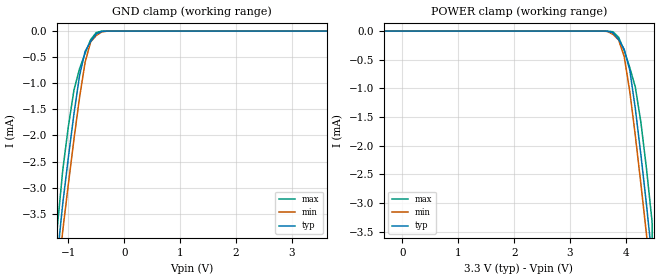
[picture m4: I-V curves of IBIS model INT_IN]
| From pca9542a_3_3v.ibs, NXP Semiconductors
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[Model]   INT_IN
Model_type Input
Vinh=2.1
Vinl=0.9
C_comp   1.73p   1.73p   1.73p
[Temperature Range] 27   85   -40
[Voltage Range]   3.3   2.97   3.63
[POWER Clamp Reference]3.3   2.97   3.63
[GND Clamp Reference]0   0   0
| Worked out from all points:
|   GND clamp passes 1 mA (typ) near -0.82 V on its own axis
[GND Clamp]
-2V       -10.28A    -9.162A    -11.7A
-1.2V     -4.351mA   -4.856mA   -3.782mA
-1.1V     -3.3mA     -3.822mA   -2.661mA
-1V       -2.42mA    -2.932mA   -1.826mA
-900mV    -1.587mA   -2.076mA   -1.131mA
-800mV    -856.5uA   -1.274mA   -722.8uA
-700mV    -388.8uA   -596.3uA   -423.6uA
-600mV    -199uA     -205.2uA   -162.8uA
-500mV    -55.95uA   -84.45uA   -27.01uA
-400mV    -5.314uA   -14.58uA   -847.7nA
-300mV    -147nA     -737.1nA   -8.808nA
3.63V     11.85pA    25pA       10.9pA
[POWER Clamp]
-330mV    11.85pA    25pA       10.9pA
3.57V     -44.33nA   -254nA     -2.09nA
3.77V     -31.95uA   -57.22uA   -11.54uA
3.87V     -148.2uA   -153.7uA   -107.4uA
3.97V     -316.4uA   -440.3uA   -335.2uA
4.07V     -678.5uA   -1.053mA   -636uA
4.17V     -1.353mA   -1.828mA   -977.2uA
4.27V     -2.164mA   -2.671mA   -1.596mA
4.37V     -3.032mA   -3.551mA   -2.402mA
4.47V     -3.974mA   -4.499mA   -3.329mA
4.57V     -7.118mA   -6.673mA   -11.82mA
5.27V     -9.706A    -8.6A      -11.12A
